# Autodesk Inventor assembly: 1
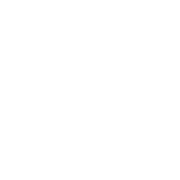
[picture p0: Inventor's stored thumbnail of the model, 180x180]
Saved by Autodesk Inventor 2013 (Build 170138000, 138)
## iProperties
Created: 2008-01
Part Number: 1
Document SubType Name: Assembly
Designer: Jürgen Wagner
Author: Jürgen Wagner
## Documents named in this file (1)
- Z:\Vorlagen\1.iam
